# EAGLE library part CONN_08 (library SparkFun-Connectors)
Multi connection point. Often used as Generic Header-pin footprint for 0.1 inch spaced/style header connections On any of the 0.1 inch spaced packages, you can populate with these: Break Away Headers - Straight (PRT-00116) Break Away Male Headers - Right Angle (PRT-00553) Female Headers (PRT-00115) Break Away Headers - Machine Pin (PRT-00117) Break Away Female Headers - Swiss Machine Pin (PRT-00743) Arduino Stackable Header - 8 Pin (PRT-09279) For SCREWTERMINALS and SPRING TERMINALS visit here: Screw Terimnals on SparkFun.com (5mm/3.5mm/2.54mm spacing) This device is also useful as a general connection point to wire up your design to another part of your project. Our various solder wires solder well into these plated through hole pads. Hook-Up Wire - Assortment (Stranded, 22 AWG) (PRT-11375) Hook-Up Wire - Assortment (Solid Core, 22 AWG) (PRT-11367) View the entire wire category on our website here Special notes: Molex polarized connector foot print use with SKU : PRT-08231 with associated crimp pins and housings. 1MM SMD Version SKU: PRT-10208 NOTES ON THE VARIANTS LOCK and LOCK_LONGPADS... This footprint was designed to help hold the alignment of a through-hole component (i.e. 6-pin header) while soldering it into place. You may notice that each hole has been shifted either up or down by 0.005 of an inch from it's more standard position (which is a perfectly straight line). This slight alteration caused the pins (the squares in the middle) to touch the edges of the holes.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

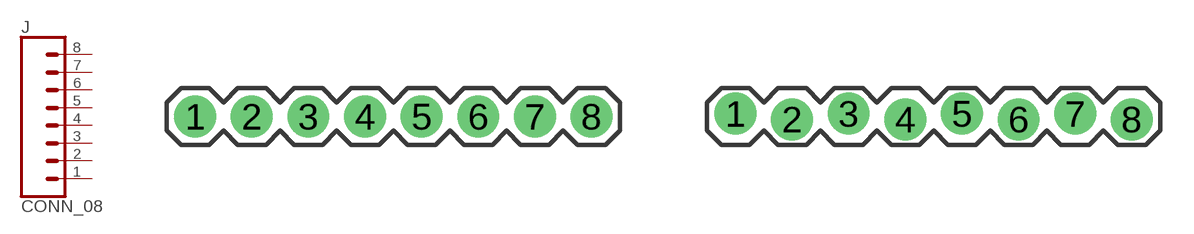
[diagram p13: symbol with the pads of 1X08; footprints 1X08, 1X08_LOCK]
Designator prefix J

## CONN_08" (PROD_ID: CONN-08438)  [1X08]
1  1  pas
2  2  pas
3  3  pas
4  4  pas
5  5  pas
6  6  pas
7  7  pas
8  8  pas

## CONN_08LOCK  [1X08_LOCK]
Pads as for 1X08

## CONN_08LOCK_LONGPADS  [1X08_LOCK_LONGPADS]
Pads as for 1X08

## CONN_08LONGPADS  [1X08_LONGPADS]
Pads as for 1X08

## CONN_083.5MM-8 (PROD_ID: Combine 14485+14885)  [SCREWTERMINAL-3.5MM-8]
Pads as for 1X08

## CONN_08SMD-STRAIGHT-FEMALE (PROD_ID: CONN-10204; SF_ID: PRT-11543)  [1X08_SMD]
Pads as for 1X08

## CONN_08SMD-STRAIGHT-ALT-FEMALE (PROD_ID: CONN-10204; SF_ID: PRT-11543)  [1X08_SMD_ALT]
Pads as for 1X08

## CONN_08SMD-COMBO-FEMALE (PROD_ID: CONN-10204; SF_ID: PRT-11543)  [1X08_SMD_COMBINED]
Pads as for 1X08

## CONN_08BM08B-SRSS-TB (PROD_ID: CONN-10556)  [BM08B-SRSS-TB]
Pads as for 1X08

## CONN_08SMD-MALE (PROD_ID: CONN-11292; SF_ID: PRT-11541)  [1X08_SMD_MALE]
Pads as for 1X08

## CONN_08NO_SILK_FEMALE_PTH (PROD_ID: CONN-08438)  [1X08_NO_SILK]
Pads as for 1X08

## CONN_08LOCK_NO_SILK  [1X08_LOCK_NO_SILK]
Pads as for 1X08

## CONN_08FEMALE_LOCK (PROD_ID: CONN-09233; SF_ID: PRT-09279)  [1X08_FEMALE_LOCK]
Pads as for 1X08

## CONN_08SMD-COMBO-FEMALE_NC (PROD_ID: CONN-10204)  [1X08_SMD_COMBINED_NC]
1  1  pas
1@2  1  pas
2  2  pas
2@2  2  pas
3  3  pas
3@2  3  pas
4  4  pas
4@2  4  pas
5  5  pas
5@2  5  pas
6  6  pas
6@2  6  pas
7  7  pas
7@2  7  pas
8  8  pas
8@2  8  pas

## CONN_08NO_SILK_DNP  [1X08_NO_SILK]
Pads as for 1X08

## Footprint 1X08 (pad centres in mm)
Plated Through Hole -8 Pin Specifications: Pin count:8 Pin pitch:0.1" Example device(s): CONN_08
drill 1.016 pad 1.88: 1 0,0; 2 2.54,0; 3 5.08,0; 4 7.62,0; 5 10.16,0; 6 12.7,0; 7 15.24,0; 8 17.78,0

## Footprint 1X08_LOCK (pad centres in mm)
Plated Through Hole -8 Pin Locking Footprint Holes are offset 0.005", to hold pins in place during soldering. Specifications: Pin count:8 Pin pitch:0.1" Example device(s): CONN_08
drill 1.016 pad 1.88: 1 0,0.127; 2 2.54,-0.127; 3 5.08,0.127; 4 7.62,-0.127; 5 10.16,0.127; 6 12.7,-0.127; 7 15.24,0.127; 8 17.78,-0.127

## Footprint 1X08_LOCK_LONGPADS (pad centres in mm)
Plated Through Hole -8 Pin Locking Footprint with Long Pads Holes are offset 0.005", to hold pins in place during soldering. Specifications: Pin count:8 Pin pitch:0.1" Example device(s): CONN_08
drill 1.016 long: 1 0,0.127; 2 2.54,-0.127; 3 5.08,0.127; 4 7.62,-0.127; 5 10.16,0.127; 6 12.7,-0.127; 7 15.24,0.127; 8 17.78,-0.127

## Footprint 1X08_LONGPADS (pad centres in mm)
Plated Through Hole -8 Pin Long Pads Specifications: Pin count:8 Pin pitch:0.1" Example device(s): CONN_08
drill 1.118 pad 1.88 long: 1 0,0; 2 2.54,0; 3 5.08,0; 4 7.62,0; 5 10.16,0; 6 12.7,0; 7 15.24,0; 8 17.78,0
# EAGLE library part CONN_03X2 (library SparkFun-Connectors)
Multi connection point. Often used as Generic Header-pin footprint for 0.1 inch spaced/style header connections You can populate with any combo of single row headers, but if you'd like an exact match, check these: Header - 2x3 (Male, 0.1") (PRT-12807) Header - 2x3 (Female, 0.1") (PRT-13010) 2x3 Pin Shrouded Header (PRT-10877) On any of the 0.1 inch spaced packages, you can populate with these: Break Away Headers - Straight (PRT-00116) Break Away Male Headers - Right Angle (PRT-00553) Female Headers (PRT-00115) Break Away Headers - Machine Pin (PRT-00117) Break Away Female Headers - Swiss Machine Pin (PRT-00743) Special note: the shrouded connector mates well with our 3x2 ribbon cables: Ribbon Crimp Connector - 6-pin (2x3, Female) (PRT-10651) Ribbon Cable - 6 wire (15ft) (PRT-10646)

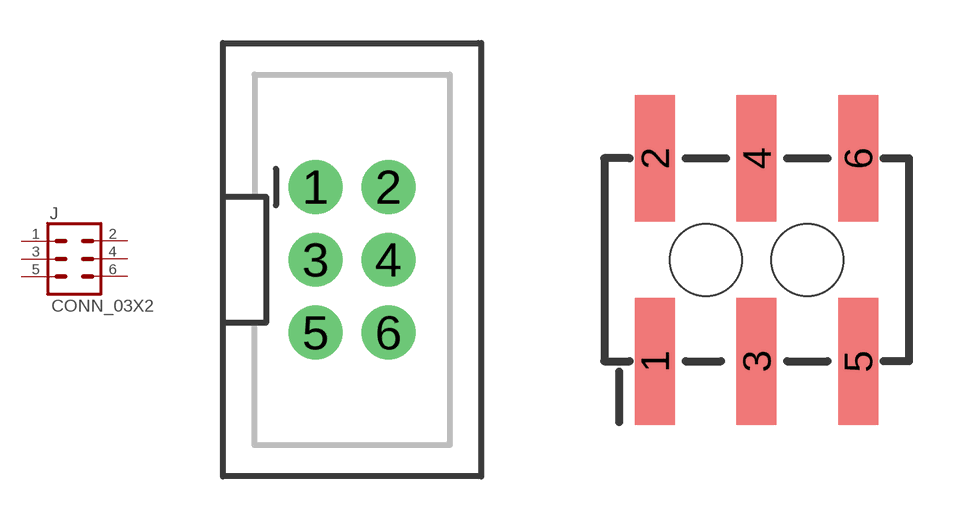
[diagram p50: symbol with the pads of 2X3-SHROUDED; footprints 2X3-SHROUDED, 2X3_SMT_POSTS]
Designator prefix J

## CONN_03X2SHROUD (PROD_ID: CONN-10681; SF_ID: PRT_10877)  [2X3-SHROUDED]
1  1
2  2
3  3
4  4
5  5
6  6

## CONN_03X2SMT (PROD_ID: CONN-11415)  [2X3_SMT_POSTS]
Pads as for 2X3-SHROUDED

## CONN_03X2POGO_PINS (PROD_ID: HW-11044)  [2X3_POGO]
P$1  1
P$2  2
P$3  3
P$4  4
P$5  5
P$6  6

## CONN_03X22X3_SILK_MALE_PTH (PROD_ID: CONN-09701)  [2X3]
Pads as for 2X3-SHROUDED

## CONN_03X2NO_SILK  [2X3-NS]
Pads as for 2X3-SHROUDED

## CONN_03X2FEMALE_SMD (PROD_ID: CONN-11290)  [2X3_SMD]
Pads as for 2X3-SHROUDED

## CONN_03X2FEMALE (PROD_ID: CONN-11566; VALUE: FEMALE 2x3)  [2X3]
Pads as for 2X3-SHROUDED

## CONN_03X22MM_PITCH (PROD_ID: CONN-14886)  [2X3_2MM]
Pads as for 2X3-SHROUDED

## Footprint 2X3-SHROUDED (pad centres in mm)
Plated Through Hole - 2x3 Shrouded Header Specifications: Pin count:6 Pin pitch:0.1" Datasheet referenced for footprint Example device(s): CONN_03x2
drill 1.016 pad 1.88: 1 -1.27,2.54; 2 1.27,2.54; 3 -1.27,0; 4 1.27,0; 5 -1.27,-2.54; 6 1.27,-2.54

## Footprint 2X3_SMT_POSTS (pad centres in mm)
Surface Mount - 2x3 Male Header with Keying Posts Specifications: Pin count:6 Pin pitch:0.1" Datasheet referenced for footprint Example device(s): CONN_03x2
smd 1 x 3.17: 1 -2.54,-2.54; 2 -2.54,2.54; 3 0,-2.54; 4 0,2.54; 5 2.54,-2.54; 6 2.54,2.54
hole 1.8 at -1.27,0
hole 1.8 at 1.27,0

## Footprint 2X3_POGO (pad centres in mm)
Plated Through Hole - 2x3 Pogo Pins Specifications: Pin count:6 Pin pitch:0.1" Example device(s): CONN_03x2
drill 1.2 pad 1.829: P$1 0,0; P$2 0,2.54; P$3 2.54,0; P$4 2.54,2.54; P$5 5.08,0; P$6 5.08,2.54

## Footprint 2X3 (pad centres in mm)
Plated Through Hole - 2x3 Specifications: Pin count:6 Pin pitch:0.1" Example device(s): CONN_03x2
drill 1.016 pad 1.88: 1 0,0; 2 0,2.54; 3 2.54,0; 4 2.54,2.54; 5 5.08,0; 6 5.08,2.54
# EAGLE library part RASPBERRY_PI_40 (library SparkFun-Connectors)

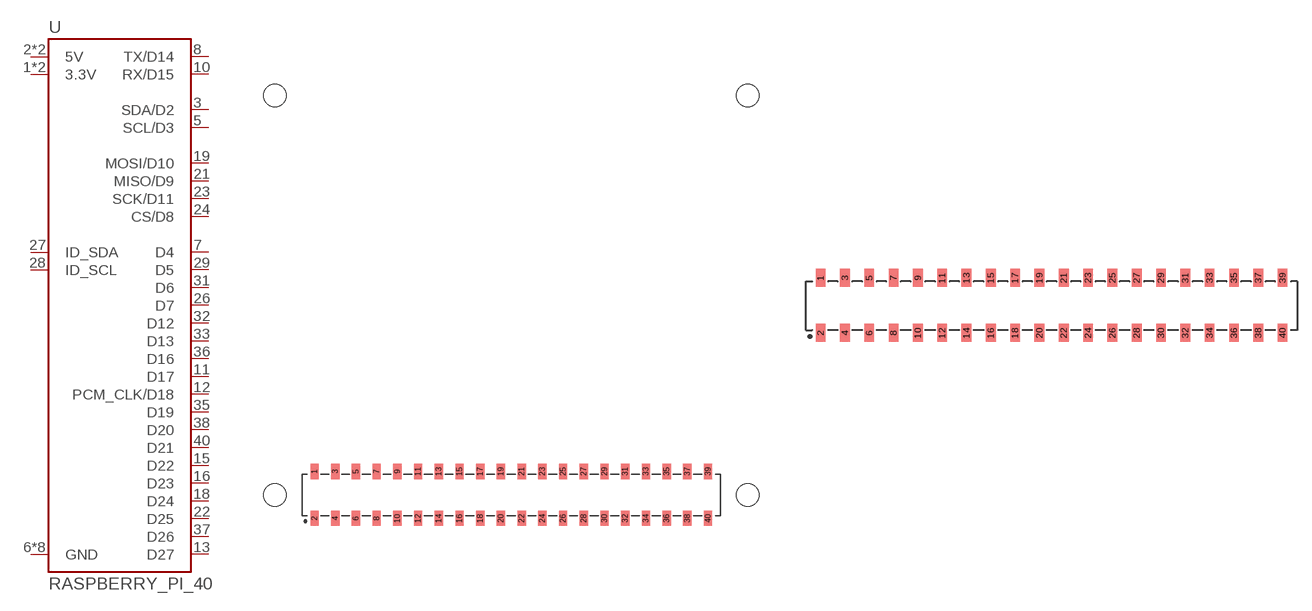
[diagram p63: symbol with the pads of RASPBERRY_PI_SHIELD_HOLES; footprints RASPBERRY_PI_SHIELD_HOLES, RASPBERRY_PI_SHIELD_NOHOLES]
Designator prefix U

## RASPBERRY_PI_40SMD  [RASPBERRY_PI_SHIELD_HOLES]
1  3.3V
2  5V
3  SDA/D2
4  5V
5  SCL/D3
6  GND
7  D4
8  TX/D14
9  GND
10  RX/D15
11  D17
12  PCM_CLK/D18
13  D27
14  GND
15  D22
16  D23
17  3.3V
18  D24
19  MOSI/D10
20  GND
21  MISO/D9
22  D25
23  SCK/D11
24  CS/D8
25  GND
26  D7
27  ID_SDA
28  ID_SCL
29  D5
30  GND
31  D6
32  D12
33  D13
34  GND
35  D19
36  D16
37  D26
38  D20
39  GND
40  D21

## RASPBERRY_PI_40NOHOLES  [RASPBERRY_PI_SHIELD_NOHOLES]
Pads as for RASPBERRY_PI_SHIELD_HOLES

## RASPBERRY_PI_40BTM-NOHOLES (PROD_ID: CONN-13790; VALUE: Raspberry Pi Header)  [RASPBERRY_PI_SHIELD_BOTTOM_ENTRY_NOHOLES]
Pads as for RASPBERRY_PI_SHIELD_HOLES

## Footprint RASPBERRY_PI_SHIELD_HOLES (pad centres in mm)
Surface Mount - 2x20 Header Reversed pinout to match Raspberry Pi male header pinout when coupled.
smd 1.02 x 1.87: 1 8.382,7.686; 2 8.382,1.929; 3 10.922,7.686; 4 10.922,1.929; 5 13.462,7.686; 6 13.462,1.929; 7 16.002,7.686; 8 16.002,1.929; 9 18.542,7.686; 10 18.542,1.929; 11 21.082,7.686; 12 21.082,1.929; 13 23.622,7.686; 14 23.622,1.929; 15 26.162,7.686; 16 26.162,1.929; 17 28.702,7.686; 18 28.702,1.929; 19 31.242,7.686; 20 31.242,1.929; 21 33.782,7.686; 22 33.782,1.929; 23 36.322,7.686; 24 36.322,1.929; 25 38.862,7.686; 26 38.862,1.929; 27 41.402,7.686; 28 41.402,1.929; 29 43.942,7.686; 30 43.942,1.929; 31 46.482,7.686; 32 46.482,1.929; 33 49.022,7.686; 34 49.022,1.929; 35 51.562,7.686; 36 51.562,1.929; 37 54.102,7.686; 38 54.102,1.929; 39 56.642,7.686; 40 56.642,1.929
hole 2.75 at 3.512,4.775
hole 2.75 at 61.512,4.775
hole 2.75 at 61.512,53.775
hole 2.75 at 3.512,53.775

## Footprint RASPBERRY_PI_SHIELD_NOHOLES (pad centres in mm)
smd 1.02 x 1.87: 1 8.382,7.686; 2 8.382,1.929; 3 10.922,7.686; 4 10.922,1.929; 5 13.462,7.686; 6 13.462,1.929; 7 16.002,7.686; 8 16.002,1.929; 9 18.542,7.686; 10 18.542,1.929; 11 21.082,7.686; 12 21.082,1.929; 13 23.622,7.686; 14 23.622,1.929; 15 26.162,7.686; 16 26.162,1.929; 17 28.702,7.686; 18 28.702,1.929; 19 31.242,7.686; 20 31.242,1.929; 21 33.782,7.686; 22 33.782,1.929; 23 36.322,7.686; 24 36.322,1.929; 25 38.862,7.686; 26 38.862,1.929; 27 41.402,7.686; 28 41.402,1.929; 29 43.942,7.686; 30 43.942,1.929; 31 46.482,7.686; 32 46.482,1.929; 33 49.022,7.686; 34 49.022,1.929; 35 51.562,7.686; 36 51.562,1.929; 37 54.102,7.686; 38 54.102,1.929; 39 56.642,7.686; 40 56.642,1.929

## Footprint RASPBERRY_PI_SHIELD_BOTTOM_ENTRY_NOHOLES (pad centres in mm)
smd 1.02 x 1.87: 1 8.37,7.665; 2 8.37,1.935; 3 10.91,7.665; 4 10.91,1.935; 5 13.45,7.665; 6 13.45,1.935; 7 15.99,7.665; 8 15.99,1.935; 9 18.53,7.665; 10 18.53,1.935; 11 21.07,7.665; 12 21.07,1.935; 13 23.61,7.665; 14 23.61,1.935; 15 26.15,7.665; 16 26.15,1.935; 17 28.69,7.665; 18 28.69,1.935; 19 31.23,7.665; 20 31.23,1.935; 21 33.77,7.665; 22 33.77,1.935; 23 36.31,7.665; 24 36.31,1.935; 25 38.85,7.665; 26 38.85,1.935; 27 41.39,7.665; 28 41.39,1.935; 29 43.93,7.665; 30 43.93,1.935; 31 46.47,7.665; 32 46.47,1.935; 33 49.01,7.665; 34 49.01,1.935; 35 51.55,7.665; 36 51.55,1.935; 37 54.09,7.665; 38 54.09,1.935; 39 56.63,7.665; 40 56.63,1.935
hole 1.02 at 31.23,6.07
hole 1.02 at 31.23,3.53
hole 1.02 at 28.69,3.53
hole 1.02 at 28.69,6.07
hole 1.02 at 26.15,6.07
hole 1.02 at 26.15,3.53
hole 1.02 at 23.61,3.53
hole 1.02 at 23.61,6.07
hole 1.02 at 36.31,6.07
hole 1.02 at 36.31,3.53
hole 1.02 at 33.77,3.53
hole 1.02 at 33.77,6.07
hole 1.02 at 15.99,6.07
hole 1.02 at 15.99,3.53
hole 1.02 at 13.45,3.53
hole 1.02 at 13.45,6.07
hole 1.02 at 10.91,6.07
hole 1.02 at 10.91,3.53
hole 1.02 at 8.37,3.53
hole 1.02 at 8.37,6.07
hole 1.02 at 21.07,6.07
hole 1.02 at 21.07,3.53
hole 1.02 at 18.53,3.53
hole 1.02 at 18.53,6.07
hole 1.02 at 46.47,6.07
hole 1.02 at 46.47,3.53
hole 1.02 at 43.93,3.53
hole 1.02 at 43.93,6.07
hole 1.02 at 41.39,6.07
hole 1.02 at 41.39,3.53
hole 1.02 at 38.85,3.53
hole 1.02 at 38.85,6.07
hole 1.02 at 51.55,6.07
hole 1.02 at 51.55,3.53
hole 1.02 at 49.01,3.53
hole 1.02 at 49.01,6.07
hole 1.02 at 54.09,6.07
hole 1.02 at 56.63,6.07
hole 1.02 at 56.63,3.53
hole 1.02 at 54.09,3.53
hole 1.8 at 55.36,4.8
hole 1.8 at 9.64,4.8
